VERSION 5.7 ;
  NOWIREEXTENSIONATPIN ON ;
  DIVIDERCHAR "/" ;
  BUSBITCHARS "[]" ;
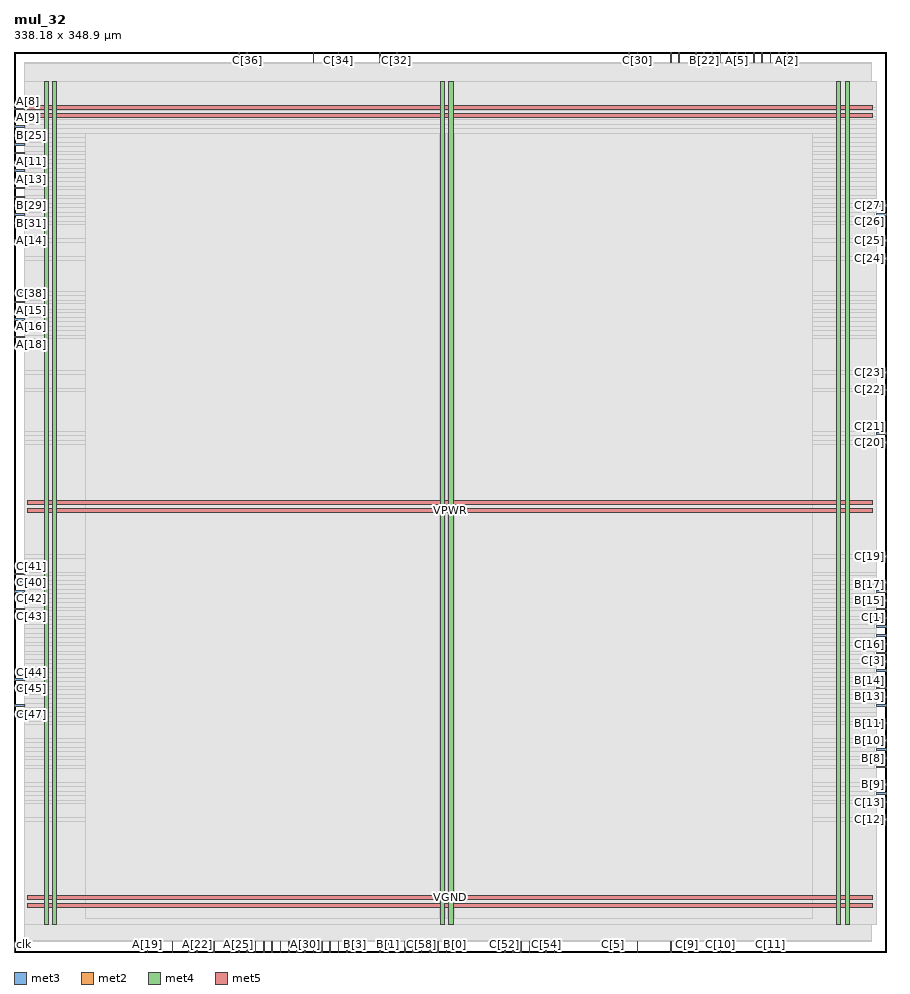
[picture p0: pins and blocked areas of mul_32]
MACRO mul_32
  CLASS BLOCK ;
  FOREIGN mul_32 ;
  ORIGIN 0.000 0.000 ;
  SIZE 338.180 BY 348.900 ;
  PIN A[0]
    DIRECTION INPUT ;
    USE SIGNAL ;
    ANTENNAGATEAREA 0.213000 ;
    PORT
      LAYER met3 ;
        RECT 334.180 61.240 338.180 61.840 ;
    END
  END A[0]
  PIN A[10]
    DIRECTION INPUT ;
    USE SIGNAL ;
    ANTENNAGATEAREA 0.196500 ;
    PORT
      LAYER met3 ;
        RECT 0.000 309.440 4.000 310.040 ;
    END
  END A[10]
  PIN A[11]
    DIRECTION INPUT ;
    USE SIGNAL ;
    ANTENNAGATEAREA 0.213000 ;
    PORT
      LAYER met3 ;
        RECT 0.000 306.040 4.000 306.640 ;
    END
  END A[11]
  PIN A[12]
    DIRECTION INPUT ;
    USE SIGNAL ;
    ANTENNAGATEAREA 0.196500 ;
    PORT
      LAYER met3 ;
        RECT 0.000 302.640 4.000 303.240 ;
    END
  END A[12]
  PIN A[13]
    DIRECTION INPUT ;
    USE SIGNAL ;
    ANTENNAGATEAREA 0.213000 ;
    PORT
      LAYER met3 ;
        RECT 0.000 299.240 4.000 299.840 ;
    END
  END A[13]
  PIN A[14]
    DIRECTION INPUT ;
    USE SIGNAL ;
    ANTENNAGATEAREA 0.196500 ;
    PORT
      LAYER met3 ;
        RECT 0.000 275.440 4.000 276.040 ;
    END
  END A[14]
  PIN A[15]
    DIRECTION INPUT ;
    USE SIGNAL ;
    ANTENNAGATEAREA 0.196500 ;
    PORT
      LAYER met3 ;
        RECT 0.000 248.240 4.000 248.840 ;
    END
  END A[15]
  PIN A[16]
    DIRECTION INPUT ;
    USE SIGNAL ;
    ANTENNAGATEAREA 0.126000 ;
    PORT
      LAYER met3 ;
        RECT 0.000 244.840 4.000 245.440 ;
    END
  END A[16]
  PIN A[17]
    DIRECTION INPUT ;
    USE SIGNAL ;
    ANTENNAGATEAREA 0.196500 ;
    PORT
      LAYER met3 ;
        RECT 0.000 241.440 4.000 242.040 ;
    END
  END A[17]
  PIN A[18]
    DIRECTION INPUT ;
    USE SIGNAL ;
    ANTENNAGATEAREA 0.126000 ;
    PORT
      LAYER met3 ;
        RECT 0.000 238.040 4.000 238.640 ;
    END
  END A[18]
  PIN A[19]
    DIRECTION INPUT ;
    USE SIGNAL ;
    ANTENNAGATEAREA 0.213000 ;
    PORT
      LAYER met2 ;
        RECT 51.610 0.000 51.890 4.000 ;
    END
  END A[19]
  PIN A[1]
    DIRECTION INPUT ;
    USE SIGNAL ;
    ANTENNAGATEAREA 0.126000 ;
    PORT
      LAYER met2 ;
        RECT 302.770 344.900 303.050 348.900 ;
    END
  END A[1]
  PIN A[20]
    DIRECTION INPUT ;
    USE SIGNAL ;
    ANTENNAGATEAREA 0.159000 ;
    PORT
      LAYER met2 ;
        RECT 61.270 0.000 61.550 4.000 ;
    END
  END A[20]
  PIN A[21]
    DIRECTION INPUT ;
    USE SIGNAL ;
    ANTENNAGATEAREA 0.159000 ;
    PORT
      LAYER met2 ;
        RECT 67.710 0.000 67.990 4.000 ;
    END
  END A[21]
  PIN A[22]
    DIRECTION INPUT ;
    USE SIGNAL ;
    ANTENNAGATEAREA 0.196500 ;
    PORT
      LAYER met2 ;
        RECT 70.930 0.000 71.210 4.000 ;
    END
  END A[22]
  PIN A[23]
    DIRECTION INPUT ;
    USE SIGNAL ;
    ANTENNAGATEAREA 0.159000 ;
    PORT
      LAYER met2 ;
        RECT 77.370 0.000 77.650 4.000 ;
    END
  END A[23]
  PIN A[24]
    DIRECTION INPUT ;
    USE SIGNAL ;
    ANTENNAGATEAREA 0.213000 ;
    PORT
      LAYER met2 ;
        RECT 83.810 0.000 84.090 4.000 ;
    END
  END A[24]
  PIN A[25]
    DIRECTION INPUT ;
    USE SIGNAL ;
    ANTENNAGATEAREA 0.213000 ;
    PORT
      LAYER met2 ;
        RECT 87.030 0.000 87.310 4.000 ;
    END
  END A[25]
  PIN A[26]
    DIRECTION INPUT ;
    USE SIGNAL ;
    ANTENNAGATEAREA 0.196500 ;
    PORT
      LAYER met2 ;
        RECT 90.250 0.000 90.530 4.000 ;
    END
  END A[26]
  PIN A[27]
    DIRECTION INPUT ;
    USE SIGNAL ;
    ANTENNAGATEAREA 0.196500 ;
    PORT
      LAYER met2 ;
        RECT 103.130 0.000 103.410 4.000 ;
    END
  END A[27]
  PIN A[28]
    DIRECTION INPUT ;
    USE SIGNAL ;
    ANTENNAGATEAREA 0.196500 ;
    PORT
      LAYER met2 ;
        RECT 122.450 0.000 122.730 4.000 ;
    END
  END A[28]
  PIN A[29]
    DIRECTION INPUT ;
    USE SIGNAL ;
    ANTENNAGATEAREA 0.213000 ;
    PORT
      LAYER met2 ;
        RECT 96.690 0.000 96.970 4.000 ;
    END
  END A[29]
  PIN A[2]
    DIRECTION INPUT ;
    USE SIGNAL ;
    ANTENNAGATEAREA 0.196500 ;
    PORT
      LAYER met2 ;
        RECT 299.550 344.900 299.830 348.900 ;
    END
  END A[2]
  PIN A[30]
    DIRECTION INPUT ;
    USE SIGNAL ;
    ANTENNAGATEAREA 0.196500 ;
    PORT
      LAYER met2 ;
        RECT 112.790 0.000 113.070 4.000 ;
    END
  END A[30]
  PIN A[31]
    DIRECTION INPUT ;
    USE SIGNAL ;
    ANTENNAGATEAREA 0.196500 ;
    PORT
      LAYER met2 ;
        RECT 106.350 0.000 106.630 4.000 ;
    END
  END A[31]
  PIN A[3]
    DIRECTION INPUT ;
    USE SIGNAL ;
    ANTENNAGATEAREA 0.159000 ;
    PORT
      LAYER met2 ;
        RECT 293.110 344.900 293.390 348.900 ;
    END
  END A[3]
  PIN A[4]
    DIRECTION INPUT ;
    USE SIGNAL ;
    ANTENNAGATEAREA 0.159000 ;
    PORT
      LAYER met2 ;
        RECT 289.890 344.900 290.170 348.900 ;
    END
  END A[4]
  PIN A[5]
    DIRECTION INPUT ;
    USE SIGNAL ;
    ANTENNAGATEAREA 0.159000 ;
    PORT
      LAYER met2 ;
        RECT 280.230 344.900 280.510 348.900 ;
    END
  END A[5]
  PIN A[6]
    DIRECTION INPUT ;
    USE SIGNAL ;
    ANTENNAGATEAREA 0.213000 ;
    PORT
      LAYER met2 ;
        RECT 273.790 344.900 274.070 348.900 ;
    END
  END A[6]
  PIN A[7]
    DIRECTION INPUT ;
    USE SIGNAL ;
    ANTENNAGATEAREA 0.196500 ;
    PORT
      LAYER met2 ;
        RECT 270.570 344.900 270.850 348.900 ;
    END
  END A[7]
  PIN A[8]
    DIRECTION INPUT ;
    USE SIGNAL ;
    ANTENNAGATEAREA 0.196500 ;
    PORT
      LAYER met3 ;
        RECT 0.000 326.440 4.000 327.040 ;
    END
  END A[8]
  PIN A[9]
    DIRECTION INPUT ;
    USE SIGNAL ;
    ANTENNAGATEAREA 0.213000 ;
    PORT
      LAYER met3 ;
        RECT 0.000 323.040 4.000 323.640 ;
    END
  END A[9]
  PIN B[0]
    DIRECTION INPUT ;
    USE SIGNAL ;
    ANTENNAGATEAREA 0.159000 ;
    PORT
      LAYER met2 ;
        RECT 170.750 0.000 171.030 4.000 ;
    END
  END B[0]
  PIN B[10]
    DIRECTION INPUT ;
    USE SIGNAL ;
    ANTENNAGATEAREA 0.213000 ;
    PORT
      LAYER met3 ;
        RECT 334.180 81.640 338.180 82.240 ;
    END
  END B[10]
  PIN B[11]
    DIRECTION INPUT ;
    USE SIGNAL ;
    ANTENNAGATEAREA 0.159000 ;
    PORT
      LAYER met3 ;
        RECT 334.180 88.440 338.180 89.040 ;
    END
  END B[11]
  PIN B[12]
    DIRECTION INPUT ;
    USE SIGNAL ;
    ANTENNAGATEAREA 0.196500 ;
    PORT
      LAYER met3 ;
        RECT 334.180 95.240 338.180 95.840 ;
    END
  END B[12]
  PIN B[13]
    DIRECTION INPUT ;
    USE SIGNAL ;
    ANTENNAGATEAREA 0.159000 ;
    PORT
      LAYER met3 ;
        RECT 334.180 98.640 338.180 99.240 ;
    END
  END B[13]
  PIN B[14]
    DIRECTION INPUT ;
    USE SIGNAL ;
    ANTENNAGATEAREA 0.213000 ;
    PORT
      LAYER met3 ;
        RECT 334.180 102.040 338.180 102.640 ;
    END
  END B[14]
  PIN B[15]
    DIRECTION INPUT ;
    USE SIGNAL ;
    ANTENNAGATEAREA 0.213000 ;
    PORT
      LAYER met3 ;
        RECT 334.180 136.040 338.180 136.640 ;
    END
  END B[15]
  PIN B[16]
    DIRECTION INPUT ;
    USE SIGNAL ;
    ANTENNAGATEAREA 0.196500 ;
    PORT
      LAYER met3 ;
        RECT 334.180 112.240 338.180 112.840 ;
    END
  END B[16]
  PIN B[17]
    DIRECTION INPUT ;
    USE SIGNAL ;
    ANTENNAGATEAREA 0.196500 ;
    PORT
      LAYER met3 ;
        RECT 334.180 139.440 338.180 140.040 ;
    END
  END B[17]
  PIN B[18]
    DIRECTION INPUT ;
    USE SIGNAL ;
    ANTENNAGATEAREA 0.213000 ;
    PORT
      LAYER met2 ;
        RECT 296.330 344.900 296.610 348.900 ;
    END
  END B[18]
  PIN B[19]
    DIRECTION INPUT ;
    USE SIGNAL ;
    ANTENNAGATEAREA 0.213000 ;
    PORT
      LAYER met2 ;
        RECT 286.670 344.900 286.950 348.900 ;
    END
  END B[19]
  PIN B[1]
    DIRECTION INPUT ;
    USE SIGNAL ;
    ANTENNAGATEAREA 0.196500 ;
    PORT
      LAYER met2 ;
        RECT 144.990 0.000 145.270 4.000 ;
    END
  END B[1]
  PIN B[20]
    DIRECTION INPUT ;
    USE SIGNAL ;
    ANTENNAGATEAREA 0.196500 ;
    PORT
      LAYER met2 ;
        RECT 283.450 344.900 283.730 348.900 ;
    END
  END B[20]
  PIN B[21]
    DIRECTION INPUT ;
    USE SIGNAL ;
    ANTENNAGATEAREA 0.196500 ;
    PORT
      LAYER met2 ;
        RECT 277.010 344.900 277.290 348.900 ;
    END
  END B[21]
  PIN B[22]
    DIRECTION INPUT ;
    USE SIGNAL ;
    ANTENNAGATEAREA 0.213000 ;
    PORT
      LAYER met2 ;
        RECT 267.350 344.900 267.630 348.900 ;
    END
  END B[22]
  PIN B[23]
    DIRECTION INPUT ;
    USE SIGNAL ;
    ANTENNAGATEAREA 0.196500 ;
    PORT
      LAYER met2 ;
        RECT 264.130 344.900 264.410 348.900 ;
    END
  END B[23]
  PIN B[24]
    DIRECTION INPUT ;
    USE SIGNAL ;
    ANTENNAGATEAREA 0.213000 ;
    PORT
      LAYER met3 ;
        RECT 0.000 319.640 4.000 320.240 ;
    END
  END B[24]
  PIN B[25]
    DIRECTION INPUT ;
    USE SIGNAL ;
    ANTENNAGATEAREA 0.196500 ;
    PORT
      LAYER met3 ;
        RECT 0.000 316.240 4.000 316.840 ;
    END
  END B[25]
  PIN B[26]
    DIRECTION INPUT ;
    USE SIGNAL ;
    ANTENNAGATEAREA 0.213000 ;
    PORT
      LAYER met3 ;
        RECT 0.000 312.840 4.000 313.440 ;
    END
  END B[26]
  PIN B[27]
    DIRECTION INPUT ;
    USE SIGNAL ;
    ANTENNAGATEAREA 0.213000 ;
    PORT
      LAYER met3 ;
        RECT 0.000 295.840 4.000 296.440 ;
    END
  END B[27]
  PIN B[28]
    DIRECTION INPUT ;
    USE SIGNAL ;
    ANTENNAGATEAREA 0.213000 ;
    PORT
      LAYER met3 ;
        RECT 0.000 292.440 4.000 293.040 ;
    END
  END B[28]
  PIN B[29]
    DIRECTION INPUT ;
    USE SIGNAL ;
    ANTENNAGATEAREA 0.213000 ;
    PORT
      LAYER met3 ;
        RECT 0.000 289.040 4.000 289.640 ;
    END
  END B[29]
  PIN B[2]
    DIRECTION INPUT ;
    USE SIGNAL ;
    ANTENNAGATEAREA 0.159000 ;
    PORT
      LAYER met2 ;
        RECT 148.210 0.000 148.490 4.000 ;
    END
  END B[2]
  PIN B[30]
    DIRECTION INPUT ;
    USE SIGNAL ;
    ANTENNAGATEAREA 0.196500 ;
    PORT
      LAYER met3 ;
        RECT 0.000 285.640 4.000 286.240 ;
    END
  END B[30]
  PIN B[31]
    DIRECTION INPUT ;
    USE SIGNAL ;
    ANTENNAGATEAREA 0.213000 ;
    PORT
      LAYER met3 ;
        RECT 0.000 282.240 4.000 282.840 ;
    END
  END B[31]
  PIN B[3]
    DIRECTION INPUT ;
    USE SIGNAL ;
    ANTENNAGATEAREA 0.213000 ;
    PORT
      LAYER met2 ;
        RECT 132.110 0.000 132.390 4.000 ;
    END
  END B[3]
  PIN B[4]
    DIRECTION INPUT ;
    USE SIGNAL ;
    ANTENNAGATEAREA 0.196500 ;
    PORT
      LAYER met2 ;
        RECT 116.010 0.000 116.290 4.000 ;
    END
  END B[4]
  PIN B[5]
    DIRECTION INPUT ;
    USE SIGNAL ;
    ANTENNAGATEAREA 0.196500 ;
    PORT
      LAYER met2 ;
        RECT 119.230 0.000 119.510 4.000 ;
    END
  END B[5]
  PIN B[6]
    DIRECTION INPUT ;
    USE SIGNAL ;
    ANTENNAGATEAREA 0.213000 ;
    PORT
      LAYER met2 ;
        RECT 128.890 0.000 129.170 4.000 ;
    END
  END B[6]
  PIN B[7]
    DIRECTION INPUT ;
    USE SIGNAL ;
    ANTENNAGATEAREA 0.213000 ;
    PORT
      LAYER met2 ;
        RECT 109.570 0.000 109.850 4.000 ;
    END
  END B[7]
  PIN B[8]
    DIRECTION INPUT ;
    USE SIGNAL ;
    ANTENNAGATEAREA 0.196500 ;
    PORT
      LAYER met3 ;
        RECT 334.180 74.840 338.180 75.440 ;
    END
  END B[8]
  PIN B[9]
    DIRECTION INPUT ;
    USE SIGNAL ;
    ANTENNAGATEAREA 0.213000 ;
    PORT
      LAYER met3 ;
        RECT 334.180 64.640 338.180 65.240 ;
    END
  END B[9]
  PIN C[0]
    DIRECTION OUTPUT ;
    USE SIGNAL ;
    ANTENNADIFFAREA 0.445500 ;
    PORT
      LAYER met3 ;
        RECT 334.180 132.640 338.180 133.240 ;
    END
  END C[0]
  PIN C[10]
    DIRECTION OUTPUT ;
    USE SIGNAL ;
    ANTENNADIFFAREA 0.445500 ;
    PORT
      LAYER met2 ;
        RECT 273.790 0.000 274.070 4.000 ;
    END
  END C[10]
  PIN C[11]
    DIRECTION OUTPUT ;
    USE SIGNAL ;
    ANTENNADIFFAREA 0.445500 ;
    PORT
      LAYER met2 ;
        RECT 293.110 0.000 293.390 4.000 ;
    END
  END C[11]
  PIN C[12]
    DIRECTION OUTPUT ;
    USE SIGNAL ;
    ANTENNADIFFAREA 0.445500 ;
    PORT
      LAYER met3 ;
        RECT 334.180 51.040 338.180 51.640 ;
    END
  END C[12]
  PIN C[13]
    DIRECTION OUTPUT ;
    USE SIGNAL ;
    ANTENNADIFFAREA 0.445500 ;
    PORT
      LAYER met3 ;
        RECT 334.180 57.840 338.180 58.440 ;
    END
  END C[13]
  PIN C[14]
    DIRECTION OUTPUT ;
    USE SIGNAL ;
    ANTENNADIFFAREA 0.445500 ;
    PORT
      LAYER met3 ;
        RECT 334.180 71.440 338.180 72.040 ;
    END
  END C[14]
  PIN C[15]
    DIRECTION OUTPUT ;
    USE SIGNAL ;
    ANTENNADIFFAREA 0.445500 ;
    PORT
      LAYER met3 ;
        RECT 334.180 78.240 338.180 78.840 ;
    END
  END C[15]
  PIN C[16]
    DIRECTION OUTPUT ;
    USE SIGNAL ;
    ANTENNADIFFAREA 0.445500 ;
    PORT
      LAYER met3 ;
        RECT 334.180 119.040 338.180 119.640 ;
    END
  END C[16]
  PIN C[17]
    DIRECTION OUTPUT ;
    USE SIGNAL ;
    ANTENNADIFFAREA 0.445500 ;
    PORT
      LAYER met3 ;
        RECT 334.180 122.440 338.180 123.040 ;
    END
  END C[17]
  PIN C[18]
    DIRECTION OUTPUT ;
    USE SIGNAL ;
    ANTENNADIFFAREA 0.445500 ;
    PORT
      LAYER met3 ;
        RECT 334.180 142.840 338.180 143.440 ;
    END
  END C[18]
  PIN C[19]
    DIRECTION OUTPUT ;
    USE SIGNAL ;
    ANTENNADIFFAREA 0.445500 ;
    PORT
      LAYER met3 ;
        RECT 334.180 153.040 338.180 153.640 ;
    END
  END C[19]
  PIN C[1]
    DIRECTION OUTPUT ;
    USE SIGNAL ;
    ANTENNADIFFAREA 0.445500 ;
    PORT
      LAYER met3 ;
        RECT 334.180 129.240 338.180 129.840 ;
    END
  END C[1]
  PIN C[20]
    DIRECTION OUTPUT ;
    USE SIGNAL ;
    ANTENNADIFFAREA 0.445500 ;
    PORT
      LAYER met3 ;
        RECT 334.180 197.240 338.180 197.840 ;
    END
  END C[20]
  PIN C[21]
    DIRECTION OUTPUT ;
    USE SIGNAL ;
    ANTENNADIFFAREA 0.445500 ;
    PORT
      LAYER met3 ;
        RECT 334.180 200.640 338.180 201.240 ;
    END
  END C[21]
  PIN C[22]
    DIRECTION OUTPUT ;
    USE SIGNAL ;
    ANTENNADIFFAREA 0.445500 ;
    PORT
      LAYER met3 ;
        RECT 334.180 217.640 338.180 218.240 ;
    END
  END C[22]
  PIN C[23]
    DIRECTION OUTPUT ;
    USE SIGNAL ;
    ANTENNADIFFAREA 0.445500 ;
    PORT
      LAYER met3 ;
        RECT 334.180 224.440 338.180 225.040 ;
    END
  END C[23]
  PIN C[24]
    DIRECTION OUTPUT ;
    USE SIGNAL ;
    ANTENNADIFFAREA 0.445500 ;
    PORT
      LAYER met3 ;
        RECT 334.180 268.640 338.180 269.240 ;
    END
  END C[24]
  PIN C[25]
    DIRECTION OUTPUT ;
    USE SIGNAL ;
    ANTENNADIFFAREA 0.445500 ;
    PORT
      LAYER met3 ;
        RECT 334.180 275.440 338.180 276.040 ;
    END
  END C[25]
  PIN C[26]
    DIRECTION OUTPUT ;
    USE SIGNAL ;
    ANTENNADIFFAREA 0.445500 ;
    PORT
      LAYER met3 ;
        RECT 334.180 285.640 338.180 286.240 ;
    END
  END C[26]
  PIN C[27]
    DIRECTION OUTPUT ;
    USE SIGNAL ;
    ANTENNADIFFAREA 0.445500 ;
    PORT
      LAYER met3 ;
        RECT 334.180 289.040 338.180 289.640 ;
    END
  END C[27]
  PIN C[28]
    DIRECTION OUTPUT ;
    USE SIGNAL ;
    ANTENNADIFFAREA 0.445500 ;
    PORT
      LAYER met2 ;
        RECT 257.690 344.900 257.970 348.900 ;
    END
  END C[28]
  PIN C[29]
    DIRECTION OUTPUT ;
    USE SIGNAL ;
    ANTENNADIFFAREA 0.445500 ;
    PORT
      LAYER met2 ;
        RECT 254.470 344.900 254.750 348.900 ;
    END
  END C[29]
  PIN C[2]
    DIRECTION OUTPUT ;
    USE SIGNAL ;
    ANTENNADIFFAREA 0.445500 ;
    PORT
      LAYER met3 ;
        RECT 334.180 125.840 338.180 126.440 ;
    END
  END C[2]
  PIN C[30]
    DIRECTION OUTPUT ;
    USE SIGNAL ;
    ANTENNADIFFAREA 0.445500 ;
    PORT
      LAYER met2 ;
        RECT 241.590 344.900 241.870 348.900 ;
    END
  END C[30]
  PIN C[31]
    DIRECTION OUTPUT ;
    USE SIGNAL ;
    ANTENNADIFFAREA 0.445500 ;
    PORT
      LAYER met2 ;
        RECT 238.370 344.900 238.650 348.900 ;
    END
  END C[31]
  PIN C[32]
    DIRECTION OUTPUT ;
    USE SIGNAL ;
    ANTENNADIFFAREA 0.445500 ;
    PORT
      LAYER met2 ;
        RECT 148.210 344.900 148.490 348.900 ;
    END
  END C[32]
  PIN C[33]
    DIRECTION OUTPUT ;
    USE SIGNAL ;
    ANTENNADIFFAREA 0.445500 ;
    PORT
      LAYER met2 ;
        RECT 141.770 344.900 142.050 348.900 ;
    END
  END C[33]
  PIN C[34]
    DIRECTION OUTPUT ;
    USE SIGNAL ;
    ANTENNADIFFAREA 0.445500 ;
    PORT
      LAYER met2 ;
        RECT 125.670 344.900 125.950 348.900 ;
    END
  END C[34]
  PIN C[35]
    DIRECTION OUTPUT ;
    USE SIGNAL ;
    ANTENNADIFFAREA 0.445500 ;
    PORT
      LAYER met2 ;
        RECT 116.010 344.900 116.290 348.900 ;
    END
  END C[35]
  PIN C[36]
    DIRECTION OUTPUT ;
    USE SIGNAL ;
    ANTENNADIFFAREA 0.445500 ;
    PORT
      LAYER met2 ;
        RECT 90.250 344.900 90.530 348.900 ;
    END
  END C[36]
  PIN C[37]
    DIRECTION OUTPUT ;
    USE SIGNAL ;
    ANTENNADIFFAREA 0.445500 ;
    PORT
      LAYER met2 ;
        RECT 87.030 344.900 87.310 348.900 ;
    END
  END C[37]
  PIN C[38]
    DIRECTION OUTPUT ;
    USE SIGNAL ;
    ANTENNADIFFAREA 0.445500 ;
    PORT
      LAYER met3 ;
        RECT 0.000 255.040 4.000 255.640 ;
    END
  END C[38]
  PIN C[39]
    DIRECTION OUTPUT ;
    USE SIGNAL ;
    ANTENNADIFFAREA 0.445500 ;
    PORT
      LAYER met3 ;
        RECT 0.000 251.640 4.000 252.240 ;
    END
  END C[39]
  PIN C[3]
    DIRECTION OUTPUT ;
    USE SIGNAL ;
    ANTENNADIFFAREA 0.445500 ;
    PORT
      LAYER met3 ;
        RECT 334.180 115.640 338.180 116.240 ;
    END
  END C[3]
  PIN C[40]
    DIRECTION OUTPUT ;
    USE SIGNAL ;
    ANTENNADIFFAREA 0.445500 ;
    PORT
      LAYER met3 ;
        RECT 0.000 142.840 4.000 143.440 ;
    END
  END C[40]
  PIN C[41]
    DIRECTION OUTPUT ;
    USE SIGNAL ;
    ANTENNADIFFAREA 0.445500 ;
    PORT
      LAYER met3 ;
        RECT 0.000 146.240 4.000 146.840 ;
    END
  END C[41]
  PIN C[42]
    DIRECTION OUTPUT ;
    USE SIGNAL ;
    ANTENNADIFFAREA 0.445500 ;
    PORT
      LAYER met3 ;
        RECT 0.000 139.440 4.000 140.040 ;
    END
  END C[42]
  PIN C[43]
    DIRECTION OUTPUT ;
    USE SIGNAL ;
    ANTENNADIFFAREA 0.445500 ;
    PORT
      LAYER met3 ;
        RECT 0.000 132.640 4.000 133.240 ;
    END
  END C[43]
  PIN C[44]
    DIRECTION OUTPUT ;
    USE SIGNAL ;
    ANTENNADIFFAREA 0.445500 ;
    PORT
      LAYER met3 ;
        RECT 0.000 105.440 4.000 106.040 ;
    END
  END C[44]
  PIN C[45]
    DIRECTION OUTPUT ;
    USE SIGNAL ;
    ANTENNADIFFAREA 0.445500 ;
    PORT
      LAYER met3 ;
        RECT 0.000 102.040 4.000 102.640 ;
    END
  END C[45]
  PIN C[46]
    DIRECTION OUTPUT ;
    USE SIGNAL ;
    ANTENNADIFFAREA 0.445500 ;
    PORT
      LAYER met3 ;
        RECT 0.000 95.240 4.000 95.840 ;
    END
  END C[46]
  PIN C[47]
    DIRECTION OUTPUT ;
    USE SIGNAL ;
    ANTENNADIFFAREA 0.445500 ;
    PORT
      LAYER met3 ;
        RECT 0.000 91.840 4.000 92.440 ;
    END
  END C[47]
  PIN C[48]
    DIRECTION OUTPUT ;
    USE SIGNAL ;
    ANTENNADIFFAREA 0.445500 ;
    PORT
      LAYER met2 ;
        RECT 164.310 0.000 164.590 4.000 ;
    END
  END C[48]
  PIN C[49]
    DIRECTION OUTPUT ;
    USE SIGNAL ;
    ANTENNADIFFAREA 0.445500 ;
    PORT
      LAYER met2 ;
        RECT 161.090 0.000 161.370 4.000 ;
    END
  END C[49]
  PIN C[4]
    DIRECTION OUTPUT ;
    USE SIGNAL ;
    ANTENNADIFFAREA 0.445500 ;
    PORT
      LAYER met3 ;
        RECT 334.180 108.840 338.180 109.440 ;
    END
  END C[4]
  PIN C[50]
    DIRECTION OUTPUT ;
    USE SIGNAL ;
    ANTENNADIFFAREA 0.445500 ;
    PORT
      LAYER met2 ;
        RECT 151.430 0.000 151.710 4.000 ;
    END
  END C[50]
  PIN C[51]
    DIRECTION OUTPUT ;
    USE SIGNAL ;
    ANTENNADIFFAREA 0.445500 ;
    PORT
      LAYER met2 ;
        RECT 167.530 0.000 167.810 4.000 ;
    END
  END C[51]
  PIN C[52]
    DIRECTION OUTPUT ;
    USE SIGNAL ;
    ANTENNADIFFAREA 0.445500 ;
    PORT
      LAYER met2 ;
        RECT 190.070 0.000 190.350 4.000 ;
    END
  END C[52]
  PIN C[53]
    DIRECTION OUTPUT ;
    USE SIGNAL ;
    ANTENNADIFFAREA 0.445500 ;
    PORT
      LAYER met2 ;
        RECT 199.730 0.000 200.010 4.000 ;
    END
  END C[53]
  PIN C[54]
    DIRECTION OUTPUT ;
    USE SIGNAL ;
    ANTENNADIFFAREA 0.445500 ;
    PORT
      LAYER met2 ;
        RECT 206.170 0.000 206.450 4.000 ;
    END
  END C[54]
  PIN C[55]
    DIRECTION OUTPUT ;
    USE SIGNAL ;
    ANTENNADIFFAREA 0.445500 ;
    PORT
      LAYER met2 ;
        RECT 209.390 0.000 209.670 4.000 ;
    END
  END C[55]
  PIN C[56]
    DIRECTION OUTPUT ;
    USE SIGNAL ;
    ANTENNADIFFAREA 0.445500 ;
    PORT
      LAYER met2 ;
        RECT 196.510 0.000 196.790 4.000 ;
    END
  END C[56]
  PIN C[57]
    DIRECTION OUTPUT ;
    USE SIGNAL ;
    ANTENNADIFFAREA 0.445500 ;
    PORT
      LAYER met2 ;
        RECT 193.290 0.000 193.570 4.000 ;
    END
  END C[57]
  PIN C[58]
    DIRECTION OUTPUT ;
    USE SIGNAL ;
    ANTENNADIFFAREA 0.445500 ;
    PORT
      LAYER met2 ;
        RECT 157.870 0.000 158.150 4.000 ;
    END
  END C[58]
  PIN C[59]
    DIRECTION OUTPUT ;
    USE SIGNAL ;
    ANTENNADIFFAREA 0.445500 ;
    PORT
      LAYER met2 ;
        RECT 154.650 0.000 154.930 4.000 ;
    END
  END C[59]
  PIN C[5]
    DIRECTION OUTPUT ;
    USE SIGNAL ;
    ANTENNADIFFAREA 0.445500 ;
    PORT
      LAYER met2 ;
        RECT 231.930 0.000 232.210 4.000 ;
    END
  END C[5]
  PIN C[60]
    DIRECTION OUTPUT ;
    USE SIGNAL ;
    ANTENNADIFFAREA 0.445500 ;
    PORT
      LAYER met2 ;
        RECT 141.770 0.000 142.050 4.000 ;
    END
  END C[60]
  PIN C[61]
    DIRECTION OUTPUT ;
    USE SIGNAL ;
    ANTENNADIFFAREA 0.445500 ;
    PORT
      LAYER met2 ;
        RECT 125.670 0.000 125.950 4.000 ;
    END
  END C[61]
  PIN C[62]
    DIRECTION OUTPUT ;
    USE SIGNAL ;
    ANTENNADIFFAREA 0.445500 ;
    PORT
      LAYER met2 ;
        RECT 99.910 0.000 100.190 4.000 ;
    END
  END C[62]
  PIN C[63]
    DIRECTION OUTPUT ;
    USE SIGNAL ;
    ANTENNADIFFAREA 0.445500 ;
    PORT
      LAYER met2 ;
        RECT 93.470 0.000 93.750 4.000 ;
    END
  END C[63]
  PIN C[6]
    DIRECTION OUTPUT ;
    USE SIGNAL ;
    ANTENNADIFFAREA 0.445500 ;
    PORT
      LAYER met2 ;
        RECT 235.150 0.000 235.430 4.000 ;
    END
  END C[6]
  PIN C[7]
    DIRECTION OUTPUT ;
    USE SIGNAL ;
    ANTENNADIFFAREA 0.445500 ;
    PORT
      LAYER met2 ;
        RECT 241.590 0.000 241.870 4.000 ;
    END
  END C[7]
  PIN C[8]
    DIRECTION OUTPUT ;
    USE SIGNAL ;
    ANTENNADIFFAREA 0.445500 ;
    PORT
      LAYER met2 ;
        RECT 254.470 0.000 254.750 4.000 ;
    END
  END C[8]
  PIN C[9]
    DIRECTION OUTPUT ;
    USE SIGNAL ;
    ANTENNADIFFAREA 0.445500 ;
    PORT
      LAYER met2 ;
        RECT 260.910 0.000 261.190 4.000 ;
    END
  END C[9]
  PIN VGND
    DIRECTION INOUT ;
    USE GROUND ;
    PORT
      LAYER met4 ;
        RECT 15.020 10.640 16.620 337.520 ;
    END
    PORT
      LAYER met4 ;
        RECT 168.620 10.640 170.220 337.520 ;
    END
    PORT
      LAYER met4 ;
        RECT 322.220 10.640 323.820 337.520 ;
    END
    PORT
      LAYER met5 ;
        RECT 5.280 20.380 332.820 21.980 ;
    END
    PORT
      LAYER met5 ;
        RECT 5.280 173.560 332.820 175.160 ;
    END
    PORT
      LAYER met5 ;
        RECT 5.280 326.740 332.820 328.340 ;
    END
  END VGND
  PIN VPWR
    DIRECTION INOUT ;
    USE POWER ;
    PORT
      LAYER met4 ;
        RECT 11.720 10.640 13.320 337.520 ;
    END
    PORT
      LAYER met4 ;
        RECT 165.320 10.640 166.920 337.520 ;
    END
    PORT
      LAYER met4 ;
        RECT 318.920 10.640 320.520 337.520 ;
    END
    PORT
      LAYER met5 ;
        RECT 5.280 17.080 332.820 18.680 ;
    END
    PORT
      LAYER met5 ;
        RECT 5.280 170.260 332.820 171.860 ;
    END
    PORT
      LAYER met5 ;
        RECT 5.280 323.440 332.820 325.040 ;
    END
  END VPWR
  PIN clk
    DIRECTION INPUT ;
    USE SIGNAL ;
    PORT
      LAYER met2 ;
        RECT 0.090 0.000 0.370 4.000 ;
    END
  END clk
  OBS
      LAYER nwell ;
        RECT 5.330 10.795 332.770 337.365 ;
      LAYER li1 ;
        RECT 5.520 10.795 332.580 337.365 ;
      LAYER met1 ;
        RECT 4.210 9.900 332.580 337.520 ;
      LAYER met2 ;
        RECT 4.230 344.620 86.750 344.900 ;
        RECT 87.590 344.620 89.970 344.900 ;
        RECT 90.810 344.620 115.730 344.900 ;
        RECT 116.570 344.620 125.390 344.900 ;
        RECT 126.230 344.620 141.490 344.900 ;
        RECT 142.330 344.620 147.930 344.900 ;
        RECT 148.770 344.620 238.090 344.900 ;
        RECT 238.930 344.620 241.310 344.900 ;
        RECT 242.150 344.620 254.190 344.900 ;
        RECT 255.030 344.620 257.410 344.900 ;
        RECT 258.250 344.620 263.850 344.900 ;
        RECT 264.690 344.620 267.070 344.900 ;
        RECT 267.910 344.620 270.290 344.900 ;
        RECT 271.130 344.620 273.510 344.900 ;
        RECT 274.350 344.620 276.730 344.900 ;
        RECT 277.570 344.620 279.950 344.900 ;
        RECT 280.790 344.620 283.170 344.900 ;
        RECT 284.010 344.620 286.390 344.900 ;
        RECT 287.230 344.620 289.610 344.900 ;
        RECT 290.450 344.620 292.830 344.900 ;
        RECT 293.670 344.620 296.050 344.900 ;
        RECT 296.890 344.620 299.270 344.900 ;
        RECT 300.110 344.620 302.490 344.900 ;
        RECT 303.330 344.620 332.490 344.900 ;
        RECT 4.230 4.280 332.490 344.620 ;
        RECT 4.230 4.000 51.330 4.280 ;
        RECT 52.170 4.000 60.990 4.280 ;
        RECT 61.830 4.000 67.430 4.280 ;
        RECT 68.270 4.000 70.650 4.280 ;
        RECT 71.490 4.000 77.090 4.280 ;
        RECT 77.930 4.000 83.530 4.280 ;
        RECT 84.370 4.000 86.750 4.280 ;
        RECT 87.590 4.000 89.970 4.280 ;
        RECT 90.810 4.000 93.190 4.280 ;
        RECT 94.030 4.000 96.410 4.280 ;
        RECT 97.250 4.000 99.630 4.280 ;
        RECT 100.470 4.000 102.850 4.280 ;
        RECT 103.690 4.000 106.070 4.280 ;
        RECT 106.910 4.000 109.290 4.280 ;
        RECT 110.130 4.000 112.510 4.280 ;
        RECT 113.350 4.000 115.730 4.280 ;
        RECT 116.570 4.000 118.950 4.280 ;
        RECT 119.790 4.000 122.170 4.280 ;
        RECT 123.010 4.000 125.390 4.280 ;
        RECT 126.230 4.000 128.610 4.280 ;
        RECT 129.450 4.000 131.830 4.280 ;
        RECT 132.670 4.000 141.490 4.280 ;
        RECT 142.330 4.000 144.710 4.280 ;
        RECT 145.550 4.000 147.930 4.280 ;
        RECT 148.770 4.000 151.150 4.280 ;
        RECT 151.990 4.000 154.370 4.280 ;
        RECT 155.210 4.000 157.590 4.280 ;
        RECT 158.430 4.000 160.810 4.280 ;
        RECT 161.650 4.000 164.030 4.280 ;
        RECT 164.870 4.000 167.250 4.280 ;
        RECT 168.090 4.000 170.470 4.280 ;
        RECT 171.310 4.000 189.790 4.280 ;
        RECT 190.630 4.000 193.010 4.280 ;
        RECT 193.850 4.000 196.230 4.280 ;
        RECT 197.070 4.000 199.450 4.280 ;
        RECT 200.290 4.000 205.890 4.280 ;
        RECT 206.730 4.000 209.110 4.280 ;
        RECT 209.950 4.000 231.650 4.280 ;
        RECT 232.490 4.000 234.870 4.280 ;
        RECT 235.710 4.000 241.310 4.280 ;
        RECT 242.150 4.000 254.190 4.280 ;
        RECT 255.030 4.000 260.630 4.280 ;
        RECT 261.470 4.000 273.510 4.280 ;
        RECT 274.350 4.000 292.830 4.280 ;
        RECT 293.670 4.000 332.490 4.280 ;
      LAYER met3 ;
        RECT 3.990 327.440 334.180 337.445 ;
        RECT 4.400 326.040 334.180 327.440 ;
        RECT 3.990 324.040 334.180 326.040 ;
        RECT 4.400 322.640 334.180 324.040 ;
        RECT 3.990 320.640 334.180 322.640 ;
        RECT 4.400 319.240 334.180 320.640 ;
        RECT 3.990 317.240 334.180 319.240 ;
        RECT 4.400 315.840 334.180 317.240 ;
        RECT 3.990 313.840 334.180 315.840 ;
        RECT 4.400 312.440 334.180 313.840 ;
        RECT 3.990 310.440 334.180 312.440 ;
        RECT 4.400 309.040 334.180 310.440 ;
        RECT 3.990 307.040 334.180 309.040 ;
        RECT 4.400 305.640 334.180 307.040 ;
        RECT 3.990 303.640 334.180 305.640 ;
        RECT 4.400 302.240 334.180 303.640 ;
        RECT 3.990 300.240 334.180 302.240 ;
        RECT 4.400 298.840 334.180 300.240 ;
        RECT 3.990 296.840 334.180 298.840 ;
        RECT 4.400 295.440 334.180 296.840 ;
        RECT 3.990 293.440 334.180 295.440 ;
        RECT 4.400 292.040 334.180 293.440 ;
        RECT 3.990 290.040 334.180 292.040 ;
        RECT 4.400 288.640 333.780 290.040 ;
        RECT 3.990 286.640 334.180 288.640 ;
        RECT 4.400 285.240 333.780 286.640 ;
        RECT 3.990 283.240 334.180 285.240 ;
        RECT 4.400 281.840 334.180 283.240 ;
        RECT 3.990 276.440 334.180 281.840 ;
        RECT 4.400 275.040 333.780 276.440 ;
        RECT 3.990 269.640 334.180 275.040 ;
        RECT 3.990 268.240 333.780 269.640 ;
        RECT 3.990 256.040 334.180 268.240 ;
        RECT 4.400 254.640 334.180 256.040 ;
        RECT 3.990 252.640 334.180 254.640 ;
        RECT 4.400 251.240 334.180 252.640 ;
        RECT 3.990 249.240 334.180 251.240 ;
        RECT 4.400 247.840 334.180 249.240 ;
        RECT 3.990 245.840 334.180 247.840 ;
        RECT 4.400 244.440 334.180 245.840 ;
        RECT 3.990 242.440 334.180 244.440 ;
        RECT 4.400 241.040 334.180 242.440 ;
        RECT 3.990 239.040 334.180 241.040 ;
        RECT 4.400 237.640 334.180 239.040 ;
        RECT 3.990 225.440 334.180 237.640 ;
        RECT 3.990 224.040 333.780 225.440 ;
        RECT 3.990 218.640 334.180 224.040 ;
        RECT 3.990 217.240 333.780 218.640 ;
        RECT 3.990 201.640 334.180 217.240 ;
        RECT 3.990 200.240 333.780 201.640 ;
        RECT 3.990 198.240 334.180 200.240 ;
        RECT 3.990 196.840 333.780 198.240 ;
        RECT 3.990 154.040 334.180 196.840 ;
        RECT 3.990 152.640 333.780 154.040 ;
        RECT 3.990 147.240 334.180 152.640 ;
        RECT 4.400 145.840 334.180 147.240 ;
        RECT 3.990 143.840 334.180 145.840 ;
        RECT 4.400 142.440 333.780 143.840 ;
        RECT 3.990 140.440 334.180 142.440 ;
        RECT 4.400 139.040 333.780 140.440 ;
        RECT 3.990 137.040 334.180 139.040 ;
        RECT 3.990 135.640 333.780 137.040 ;
        RECT 3.990 133.640 334.180 135.640 ;
        RECT 4.400 132.240 333.780 133.640 ;
        RECT 3.990 130.240 334.180 132.240 ;
        RECT 3.990 128.840 333.780 130.240 ;
        RECT 3.990 126.840 334.180 128.840 ;
        RECT 3.990 125.440 333.780 126.840 ;
        RECT 3.990 123.440 334.180 125.440 ;
        RECT 3.990 122.040 333.780 123.440 ;
        RECT 3.990 120.040 334.180 122.040 ;
        RECT 3.990 118.640 333.780 120.040 ;
        RECT 3.990 116.640 334.180 118.640 ;
        RECT 3.990 115.240 333.780 116.640 ;
        RECT 3.990 113.240 334.180 115.240 ;
        RECT 3.990 111.840 333.780 113.240 ;
        RECT 3.990 109.840 334.180 111.840 ;
        RECT 3.990 108.440 333.780 109.840 ;
        RECT 3.990 106.440 334.180 108.440 ;
        RECT 4.400 105.040 334.180 106.440 ;
        RECT 3.990 103.040 334.180 105.040 ;
        RECT 4.400 101.640 333.780 103.040 ;
        RECT 3.990 99.640 334.180 101.640 ;
        RECT 3.990 98.240 333.780 99.640 ;
        RECT 3.990 96.240 334.180 98.240 ;
        RECT 4.400 94.840 333.780 96.240 ;
        RECT 3.990 92.840 334.180 94.840 ;
        RECT 4.400 91.440 334.180 92.840 ;
        RECT 3.990 89.440 334.180 91.440 ;
        RECT 3.990 88.040 333.780 89.440 ;
        RECT 3.990 82.640 334.180 88.040 ;
        RECT 3.990 81.240 333.780 82.640 ;
        RECT 3.990 79.240 334.180 81.240 ;
        RECT 3.990 77.840 333.780 79.240 ;
        RECT 3.990 75.840 334.180 77.840 ;
        RECT 3.990 74.440 333.780 75.840 ;
        RECT 3.990 72.440 334.180 74.440 ;
        RECT 3.990 71.040 333.780 72.440 ;
        RECT 3.990 65.640 334.180 71.040 ;
        RECT 3.990 64.240 333.780 65.640 ;
        RECT 3.990 62.240 334.180 64.240 ;
        RECT 3.990 60.840 333.780 62.240 ;
        RECT 3.990 58.840 334.180 60.840 ;
        RECT 3.990 57.440 333.780 58.840 ;
        RECT 3.990 52.040 334.180 57.440 ;
        RECT 3.990 50.640 333.780 52.040 ;
        RECT 3.990 10.715 334.180 50.640 ;
      LAYER met4 ;
        RECT 27.895 13.095 164.920 317.385 ;
        RECT 167.320 13.095 168.220 317.385 ;
        RECT 170.620 13.095 309.745 317.385 ;
  END
END mul_32
END LIBRARY

